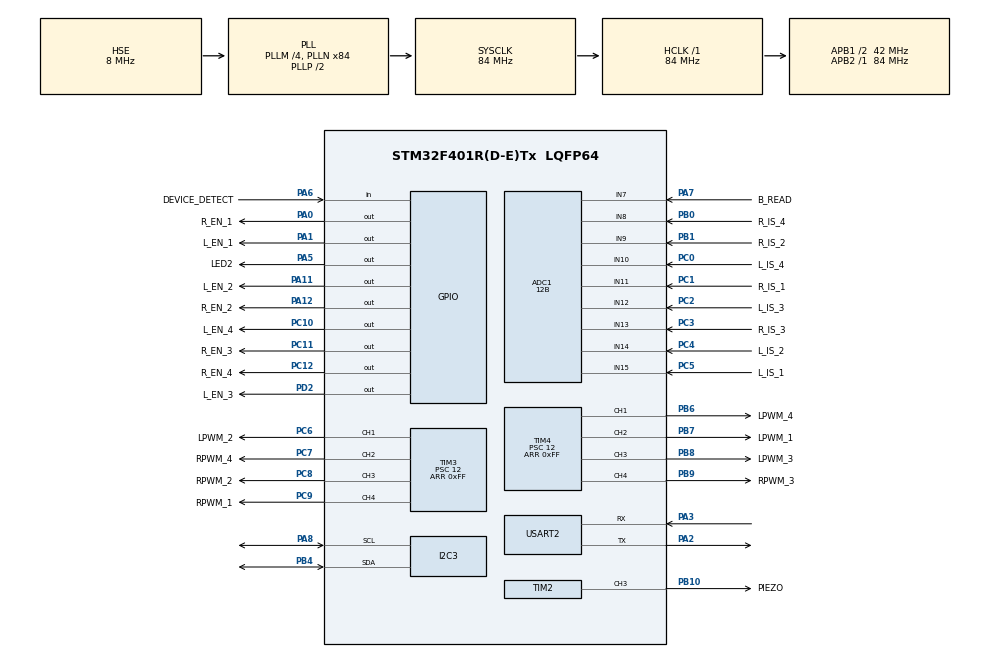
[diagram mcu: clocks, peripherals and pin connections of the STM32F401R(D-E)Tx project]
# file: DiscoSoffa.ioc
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ADC1.Channel-10\#ChannelRegularConversion=ADC_CHANNEL_13
ADC1.Channel-11\#ChannelRegularConversion=ADC_CHANNEL_14
ADC1.Channel-12\#ChannelRegularConversion=ADC_CHANNEL_15
ADC1.Channel-4\#ChannelRegularConversion=ADC_CHANNEL_7
ADC1.Channel-5\#ChannelRegularConversion=ADC_CHANNEL_8
ADC1.Channel-6\#ChannelRegularConversion=ADC_CHANNEL_9
ADC1.Channel-7\#ChannelRegularConversion=ADC_CHANNEL_10
ADC1.Channel-8\#ChannelRegularConversion=ADC_CHANNEL_11
ADC1.Channel-9\#ChannelRegularConversion=ADC_CHANNEL_12
ADC1.ContinuousConvMode=ENABLE
ADC1.DMAContinuousRequests=ENABLE
ADC1.NbrOfConversion=9
ADC1.NbrOfConversionFlag=1
ADC1.Rank-10\#ChannelRegularConversion=7
ADC1.Rank-11\#ChannelRegularConversion=8
ADC1.Rank-12\#ChannelRegularConversion=9
ADC1.Rank-4\#ChannelRegularConversion=1
ADC1.Rank-5\#ChannelRegularConversion=2
ADC1.Rank-6\#ChannelRegularConversion=3
ADC1.Rank-7\#ChannelRegularConversion=4
ADC1.Rank-8\#ChannelRegularConversion=5
ADC1.Rank-9\#ChannelRegularConversion=6
ADC1.Resolution=ADC_RESOLUTION_12B
ADC1.SamplingTime-10\#ChannelRegularConversion=ADC_SAMPLETIME_56CYCLES
ADC1.SamplingTime-11\#ChannelRegularConversion=ADC_SAMPLETIME_56CYCLES
ADC1.SamplingTime-12\#ChannelRegularConversion=ADC_SAMPLETIME_56CYCLES
ADC1.SamplingTime-4\#ChannelRegularConversion=ADC_SAMPLETIME_56CYCLES
ADC1.SamplingTime-5\#ChannelRegularConversion=ADC_SAMPLETIME_56CYCLES
ADC1.SamplingTime-6\#ChannelRegularConversion=ADC_SAMPLETIME_56CYCLES
ADC1.SamplingTime-7\#ChannelRegularConversion=ADC_SAMPLETIME_56CYCLES
ADC1.SamplingTime-8\#ChannelRegularConversion=ADC_SAMPLETIME_56CYCLES
ADC1.SamplingTime-9\#ChannelRegularConversion=ADC_SAMPLETIME_56CYCLES
ADC1.ScanConvMode=ENABLE
ADC1.master=1
Dma.ADC1.0.Direction=DMA_PERIPH_TO_MEMORY
Dma.ADC1.0.FIFOMode=DMA_FIFOMODE_DISABLE
Dma.ADC1.0.Instance=DMA2_Stream0
Dma.ADC1.0.MemDataAlignment=DMA_MDATAALIGN_HALFWORD
Dma.ADC1.0.MemInc=DMA_MINC_ENABLE
Dma.ADC1.0.Mode=DMA_CIRCULAR
Dma.ADC1.0.PeriphDataAlignment=DMA_PDATAALIGN_HALFWORD
Dma.ADC1.0.PeriphInc=DMA_PINC_DISABLE
Dma.ADC1.0.Priority=DMA_PRIORITY_HIGH
Dma.Request0=ADC1
Mcu.Family=STM32F4
Mcu.Name=STM32F401R(D-E)Tx
Mcu.Package=LQFP64
NVIC.ADC_IRQn=true\:0\:0\:false\:false\:true\:true\:true
NVIC.DMA2_Stream0_IRQn=true\:0\:0\:false\:false\:true\:false\:true
NVIC.I2C3_ER_IRQn=true\:0\:0\:false\:false\:true\:true\:true
NVIC.I2C3_EV_IRQn=true\:0\:0\:false\:false\:true\:true\:true
NVIC.PriorityGroup=NVIC_PRIORITYGROUP_4
PA0-WKUP.GPIO_Label=R_EN_1
PA0-WKUP.Signal=GPIO_Output
PA1.GPIO_Label=L_EN_1
PA1.Signal=GPIO_Output
PA11.GPIO_Label=L_EN_2
PA11.Signal=GPIO_Output
PA12.GPIO_Label=R_EN_2
PA12.Signal=GPIO_Output
PA13.Mode=Trace_Asynchronous_SW
PA13.Signal=SYS_JTMS-SWDIO
PA14.Mode=Trace_Asynchronous_SW
PA14.Signal=SYS_JTCK-SWCLK
PA2.Mode=Asynchronous
PA2.Signal=USART2_TX
PA3.Mode=Asynchronous
PA3.Signal=USART2_RX
PA5.GPIO_Label=LED2
PA5.Signal=GPIO_Output
PA6.GPIO_Label=DEVICE_DETECT
PA6.Signal=GPIO_Input
PA7.GPIO_Label=B_READ
PA7.Signal=ADCx_IN7
PA8.Mode=I2C
PA8.Signal=I2C3_SCL
PB0.GPIO_Label=R_IS_4
PB0.Signal=ADCx_IN8
PB1.GPIO_Label=R_IS_2
PB1.Signal=ADCx_IN9
PB10.GPIO_Label=PIEZO
PB10.Signal=S_TIM2_CH3
PB3.Mode=Trace_Asynchronous_SW
PB3.Signal=SYS_JTDO-SWO
PB4.Mode=I2C
PB4.Signal=I2C3_SDA
PB6.GPIO_Label=LPWM_4
PB6.Signal=S_TIM4_CH1
PB7.GPIO_Label=LPWM_1
PB7.Signal=S_TIM4_CH2
PB8.GPIO_Label=LPWM_3
PB8.Signal=S_TIM4_CH3
PB9.GPIO_Label=RPWM_3
PB9.Signal=S_TIM4_CH4
PC0.GPIO_Label=L_IS_4
PC0.Signal=ADCx_IN10
PC1.GPIO_Label=R_IS_1
PC1.Signal=ADCx_IN11
PC10.GPIO_Label=L_EN_4
PC10.Signal=GPIO_Output
PC11.GPIO_Label=R_EN_3
PC11.Signal=GPIO_Output
PC12.GPIO_Label=R_EN_4
PC12.Signal=GPIO_Output
PC2.GPIO_Label=L_IS_3
PC2.Signal=ADCx_IN12
PC3.GPIO_Label=R_IS_3
PC3.Signal=ADCx_IN13
PC4.GPIO_Label=L_IS_2
PC4.Signal=ADCx_IN14
PC5.GPIO_Label=L_IS_1
PC5.Signal=ADCx_IN15
PC6.GPIO_Label=LPWM_2
PC6.Signal=S_TIM3_CH1
PC7.GPIO_Label=RPWM_4
PC7.Signal=S_TIM3_CH2
PC8.GPIO_Label=RPWM_2
PC8.Signal=S_TIM3_CH3
PC9.GPIO_Label=RPWM_1
PC9.Signal=S_TIM3_CH4
PD2.GPIO_Label=L_EN_3
PD2.Signal=GPIO_Output
PH0\ -\ OSC_IN.Mode=HSE-External-Clock-Source
PH0\ -\ OSC_IN.Signal=RCC_OSC_IN
PH1\ -\ OSC_OUT.Mode=HSE-External-Clock-Source
PH1\ -\ OSC_OUT.Signal=RCC_OSC_OUT
ProjectManager.HeapSize=0x200
ProjectManager.StackSize=0x400
ProjectManager.TargetToolchain=TrueSTUDIO
RCC.48MHZClocksFreq_Value=42000000
RCC.AHBFreq_Value=84000000
RCC.APB1CLKDivider=RCC_HCLK_DIV2
RCC.APB1Freq_Value=42000000
RCC.APB1TimFreq_Value=84000000
RCC.APB2Freq_Value=84000000
RCC.APB2TimFreq_Value=84000000
RCC.CortexFreq_Value=84000000
RCC.HCLKFreq_Value=84000000
RCC.HSE_VALUE=8000000
RCC.HSI_VALUE=16000000
RCC.LSE_VALUE=32768
RCC.PLLM=4
RCC.PLLN=84
RCC.PLLSourceVirtual=RCC_PLLSOURCE_HSE
RCC.SYSCLKFreq_VALUE=84000000
RCC.SYSCLKSource=RCC_SYSCLKSOURCE_PLLCLK
RCC.VCOOutputFreq_Value=168000000
SH.ADCx_IN10.0=ADC1_IN10,IN10
SH.ADCx_IN11.0=ADC1_IN11,IN11
SH.ADCx_IN12.0=ADC1_IN12,IN12
SH.ADCx_IN13.0=ADC1_IN13,IN13
SH.ADCx_IN14.0=ADC1_IN14,IN14
SH.ADCx_IN15.0=ADC1_IN15,IN15
SH.ADCx_IN7.0=ADC1_IN7,IN7
SH.ADCx_IN8.0=ADC1_IN8,IN8
SH.ADCx_IN9.0=ADC1_IN9,IN9
SH.S_TIM2_CH3.0=TIM2_CH3,PWM Generation3 CH3
SH.S_TIM3_CH1.0=TIM3_CH1,PWM Generation1 CH1
SH.S_TIM3_CH2.0=TIM3_CH2,PWM Generation2 CH2
SH.S_TIM3_CH3.0=TIM3_CH3,PWM Generation3 CH3
SH.S_TIM3_CH4.0=TIM3_CH4,PWM Generation4 CH4
SH.S_TIM4_CH1.0=TIM4_CH1,PWM Generation1 CH1
SH.S_TIM4_CH2.0=TIM4_CH2,PWM Generation2 CH2
SH.S_TIM4_CH3.0=TIM4_CH3,PWM Generation3 CH3
SH.S_TIM4_CH4.0=TIM4_CH4,PWM Generation4 CH4
TIM2.Channel-PWM\ Generation3\ CH3=TIM_CHANNEL_3
TIM2.OCFastMode_PWM-PWM\ Generation3\ CH3=TIM_OCFAST_ENABLE
TIM2.Period=65536
TIM2.Pulse-PWM\ Generation3\ CH3=32768
TIM3.Channel-PWM\ Generation1\ CH1=TIM_CHANNEL_1
TIM3.Channel-PWM\ Generation2\ CH2=TIM_CHANNEL_2
TIM3.Channel-PWM\ Generation3\ CH3=TIM_CHANNEL_3
TIM3.Channel-PWM\ Generation4\ CH4=TIM_CHANNEL_4
TIM3.OCFastMode_PWM-PWM\ Generation1\ CH1=TIM_OCFAST_ENABLE
TIM3.OCFastMode_PWM-PWM\ Generation2\ CH2=TIM_OCFAST_ENABLE
TIM3.OCFastMode_PWM-PWM\ Generation3\ CH3=TIM_OCFAST_ENABLE
TIM3.OCFastMode_PWM-PWM\ Generation4\ CH4=TIM_OCFAST_ENABLE
TIM3.Period=0xFF
TIM3.Prescaler=12
TIM3.Pulse-PWM\ Generation1\ CH1=0x80
TIM4.Channel-PWM\ Generation1\ CH1=TIM_CHANNEL_1
TIM4.Channel-PWM\ Generation2\ CH2=TIM_CHANNEL_2
TIM4.Channel-PWM\ Generation3\ CH3=TIM_CHANNEL_3
TIM4.Channel-PWM\ Generation4\ CH4=TIM_CHANNEL_4
TIM4.OCFastMode_PWM-PWM\ Generation1\ CH1=TIM_OCFAST_ENABLE
TIM4.OCFastMode_PWM-PWM\ Generation2\ CH2=TIM_OCFAST_ENABLE
TIM4.OCFastMode_PWM-PWM\ Generation3\ CH3=TIM_OCFAST_ENABLE
TIM4.OCFastMode_PWM-PWM\ Generation4\ CH4=TIM_OCFAST_ENABLE
TIM4.Period=0xFF
TIM4.Prescaler=12
USART2.VirtualMode=VM_ASYNC
VP_TIM2_VS_ClockSourceINT.Mode=Internal
VP_TIM3_VS_ClockSourceINT.Mode=Internal
VP_TIM4_VS_ClockSourceINT.Mode=Internal
board=custom

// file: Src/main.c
/* USER CODE BEGIN Header */
/**
  ******************************************************************************
  * @file           : main.c
  * @brief          : Main program body
  ******************************************************************************
  * @attention
  *
  * <h2><center>&copy; Copyright (c) 2019 STMicroelectronics.
  * All rights reserved.</center></h2>
  *
  * This software component is licensed by ST under BSD 3-Clause license,
  * the "License"; You may not use this file except in compliance with the
  * License. You may obtain a copy of the License at:
  *                        opensource.org/licenses/BSD-3-Clause
  *
  ******************************************************************************
  */
/* USER CODE END Header */

#include "main.h"

ADC_HandleTypeDef hadc1;
DMA_HandleTypeDef hdma_adc1;

I2C_HandleTypeDef hi2c3;

TIM_HandleTypeDef htim2;
TIM_HandleTypeDef htim3;
TIM_HandleTypeDef htim4;

UART_HandleTypeDef huart2;

/* USER CODE BEGIN PV */

NUNCHUCK_HandleTypeDef nun1;

MOTOR_HandleTypeDef motor1;
MOTOR_HandleTypeDef motor2;
MOTOR_HandleTypeDef motor3;
MOTOR_HandleTypeDef motor4;

BOARD_BuzzerHandlerTypeDef buzzer;
BOARD_BatteryVoltageHandlerTypedef hbat;

uint8_t uartBuffer[50];
uint16_t adcBuffer[9];

uint8_t speed;
uint8_t leftSpeed;
uint8_t rightSpeed;

MOTOR_ModeTypeDef motorMode;

/* USER CODE END PV */

void SystemClock_Config(void);
static void MX_GPIO_Init(void);
static void MX_DMA_Init(void);
static void MX_ADC1_Init(void);
static void MX_I2C3_Init(void);
static void MX_TIM2_Init(void);
static void MX_TIM3_Init(void);
static void MX_TIM4_Init(void);
static void MX_USART2_UART_Init(void);
/* USER CODE BEGIN PFP */

static void MX_BOARD_Init(void);
static void MX_MOTOR_Init(void);
static void MX_NUNCHUCK_Init(void);

/* USER CODE END PFP */

int main(void)
{

  /* MCU Configuration--------------------------------------------------------*/

  /* Reset of all peripherals, Initializes the Flash interface and the Systick. */
  HAL_Init();

  /* Configure the system clock */
  SystemClock_Config();

  /* Initialize all configured peripherals */
  MX_GPIO_Init();
  MX_DMA_Init();
  MX_ADC1_Init();
  MX_I2C3_Init();
  MX_TIM2_Init();
  MX_TIM3_Init();
  MX_TIM4_Init();
  MX_USART2_UART_Init();
  /* USER CODE BEGIN 2 */
  /* Initialize drivers */
  MX_BOARD_Init();
  MX_MOTOR_Init();
  MX_NUNCHUCK_Init();

  /* Play startup sound */
  HAL_BOARD_BuzzerBeep(&buzzer,440,200);
  HAL_BOARD_BuzzerBeep(&buzzer,440*2,200);
  HAL_BOARD_BuzzerBeep(&buzzer,440*3,200);
  HAL_BOARD_BuzzerBeep(&buzzer,440*4,200);
  HAL_BOARD_BuzzerBeep(&buzzer,440,300);

  /* Start ADC DMA */
  HAL_ADC_Start_DMA(&hadc1, (uint32_t *) adcBuffer, 9);

  /* USER CODE END 2 */

  /* Infinite loop */
  while (1)
  {

    /* USER CODE BEGIN 3 */

	  HAL_NUNCHUCK_Read(&nun1);

	  if(nun1.Connected != 1)
	  {
		  if((nun1.zButton != 1) || (nun1.cButton == 1))
		  {
			  motorMode = HAL_MOTOR_MODE_BREAK;
		  }
		  else if(nun1.yJoy == 0)
		  {
			  motorMode = HAL_MOTOR_MODE_DISABLE;
		  }
		  else if(nun1.yJoy > 0)
		  {
			  motorMode = HAL_MOTOR_MODE_FORWARD;
			  speed = nun1.yJoy*0xFF;
		  }
		  else if(nun1.yJoy < 0)
		  {
			  motorMode = HAL_MOTOR_MODE_REVERSE;
			  speed = -nun1.yJoy*0xFF;
		  }

		  if(nun1.xJoy > 0)
		  {
			  leftSpeed = speed;
			  rightSpeed = (1.0f-nun1.xJoy)*speed;
		  }
		  else if(nun1.xJoy < 0)
		  {
			  rightSpeed = speed;
			  leftSpeed = (1.0f+nun1.xJoy)*speed;
		  }
		  else
		  {
			  rightSpeed = speed;
			  leftSpeed = speed;
		  }
	  }
	  else
	  {
		  motorMode = HAL_MOTOR_MODE_BREAK;
		  speed = 0;
		  rightSpeed = 0;
		  leftSpeed = 0;
	  }
	  motor1.TargetDuty = rightSpeed;
	  motor3.TargetDuty = rightSpeed;

	  motor2.TargetDuty = leftSpeed;
	  motor4.TargetDuty = leftSpeed;

	  motor1.TargetMotorMode = motorMode;
	  motor2.TargetMotorMode = motorMode;
	  motor3.TargetMotorMode = motorMode;
	  motor4.TargetMotorMode = motorMode;

	  HAL_MOTOR_Update(&motor1);
	  HAL_MOTOR_Update(&motor2);
	  HAL_MOTOR_Update(&motor3);
	  HAL_MOTOR_Update(&motor4);

	  HAL_Delay(20);
  }
  /* USER CODE END 3 */
}

void SystemClock_Config(void)
{
  RCC_OscInitTypeDef RCC_OscInitStruct = {0};
  RCC_ClkInitTypeDef RCC_ClkInitStruct = {0};

  /** Configure the main internal regulator output voltage
  */
  __HAL_RCC_PWR_CLK_ENABLE();
  __HAL_PWR_VOLTAGESCALING_CONFIG(PWR_REGULATOR_VOLTAGE_SCALE2);
  /** Initializes the CPU, AHB and APB busses clocks
  */
  RCC_OscInitStruct.OscillatorType = RCC_OSCILLATORTYPE_HSE;
  RCC_OscInitStruct.HSEState = RCC_HSE_BYPASS;
  RCC_OscInitStruct.PLL.PLLState = RCC_PLL_ON;
  RCC_OscInitStruct.PLL.PLLSource = RCC_PLLSOURCE_HSE;
  RCC_OscInitStruct.PLL.PLLM = 4;
  RCC_OscInitStruct.PLL.PLLN = 84;
  RCC_OscInitStruct.PLL.PLLP = RCC_PLLP_DIV2;
  RCC_OscInitStruct.PLL.PLLQ = 4;
  if (HAL_RCC_OscConfig(&RCC_OscInitStruct) != HAL_OK)
  {
    Error_Handler();
  }
  /** Initializes the CPU, AHB and APB busses clocks
  */
  RCC_ClkInitStruct.ClockType = RCC_CLOCKTYPE_HCLK|RCC_CLOCKTYPE_SYSCLK
                              |RCC_CLOCKTYPE_PCLK1|RCC_CLOCKTYPE_PCLK2;
  RCC_ClkInitStruct.SYSCLKSource = RCC_SYSCLKSOURCE_PLLCLK;
  RCC_ClkInitStruct.AHBCLKDivider = RCC_SYSCLK_DIV1;
  RCC_ClkInitStruct.APB1CLKDivider = RCC_HCLK_DIV2;
  RCC_ClkInitStruct.APB2CLKDivider = RCC_HCLK_DIV1;

  if (HAL_RCC_ClockConfig(&RCC_ClkInitStruct, FLASH_LATENCY_2) != HAL_OK)
  {
    Error_Handler();
  }
}

static void MX_ADC1_Init(void)
{

  ADC_ChannelConfTypeDef sConfig = {0};

  /** Configure the global features of the ADC (Clock, Resolution, Data Alignment and number of conversion)
  */
  hadc1.Instance = ADC1;
  hadc1.Init.ClockPrescaler = ADC_CLOCK_SYNC_PCLK_DIV4;
  hadc1.Init.Resolution = ADC_RESOLUTION_12B;
  hadc1.Init.ScanConvMode = ENABLE;
  hadc1.Init.ContinuousConvMode = ENABLE;
  hadc1.Init.DiscontinuousConvMode = DISABLE;
  hadc1.Init.ExternalTrigConvEdge = ADC_EXTERNALTRIGCONVEDGE_NONE;
  hadc1.Init.ExternalTrigConv = ADC_SOFTWARE_START;
  hadc1.Init.DataAlign = ADC_DATAALIGN_RIGHT;
  hadc1.Init.NbrOfConversion = 9;
  hadc1.Init.DMAContinuousRequests = ENABLE;
  hadc1.Init.EOCSelection = ADC_EOC_SINGLE_CONV;
  if (HAL_ADC_Init(&hadc1) != HAL_OK)
  {
    Error_Handler();
  }
  /** Configure for the selected ADC regular channel its corresponding rank in the sequencer and its sample time.
  */
  sConfig.Channel = ADC_CHANNEL_7;
  sConfig.Rank = 1;
  sConfig.SamplingTime = ADC_SAMPLETIME_56CYCLES;
  if (HAL_ADC_ConfigChannel(&hadc1, &sConfig) != HAL_OK)
  {
    Error_Handler();
  }
  /** Configure for the selected ADC regular channel its corresponding rank in the sequencer and its sample time.
  */
  sConfig.Channel = ADC_CHANNEL_8;
  sConfig.Rank = 2;
  if (HAL_ADC_ConfigChannel(&hadc1, &sConfig) != HAL_OK)
  {
    Error_Handler();
  }
  /** Configure for the selected ADC regular channel its corresponding rank in the sequencer and its sample time.
  */
  sConfig.Channel = ADC_CHANNEL_9;
  sConfig.Rank = 3;
  if (HAL_ADC_ConfigChannel(&hadc1, &sConfig) != HAL_OK)
  {
    Error_Handler();
  }
  /** Configure for the selected ADC regular channel its corresponding rank in the sequencer and its sample time.
  */
  sConfig.Channel = ADC_CHANNEL_10;
  sConfig.Rank = 4;
  if (HAL_ADC_ConfigChannel(&hadc1, &sConfig) != HAL_OK)
  {
    Error_Handler();
  }
  /** Configure for the selected ADC regular channel its corresponding rank in the sequencer and its sample time.
  */
  sConfig.Channel = ADC_CHANNEL_11;
  sConfig.Rank = 5;
  if (HAL_ADC_ConfigChannel(&hadc1, &sConfig) != HAL_OK)
  {
    Error_Handler();
  }
  /** Configure for the selected ADC regular channel its corresponding rank in the sequencer and its sample time.
  */
  sConfig.Channel = ADC_CHANNEL_12;
  sConfig.Rank = 6;
  if (HAL_ADC_ConfigChannel(&hadc1, &sConfig) != HAL_OK)
  {
    Error_Handler();
  }
  /** Configure for the selected ADC regular channel its corresponding rank in the sequencer and its sample time.
  */
  sConfig.Channel = ADC_CHANNEL_13;
  sConfig.Rank = 7;
  if (HAL_ADC_ConfigChannel(&hadc1, &sConfig) != HAL_OK)
  {
    Error_Handler();
  }
  /** Configure for the selected ADC regular channel its corresponding rank in the sequencer and its sample time.
  */
  sConfig.Channel = ADC_CHANNEL_14;
  sConfig.Rank = 8;
  if (HAL_ADC_ConfigChannel(&hadc1, &sConfig) != HAL_OK)
  {
    Error_Handler();
  }
  /** Configure for the selected ADC regular channel its corresponding rank in the sequencer and its sample time.
  */
  sConfig.Channel = ADC_CHANNEL_15;
  sConfig.Rank = 9;
  if (HAL_ADC_ConfigChannel(&hadc1, &sConfig) != HAL_OK)
  {
    Error_Handler();
  }

}

static void MX_I2C3_Init(void)
{

  hi2c3.Instance = I2C3;
  hi2c3.Init.ClockSpeed = 100000;
  hi2c3.Init.DutyCycle = I2C_DUTYCYCLE_2;
  hi2c3.Init.OwnAddress1 = 0;
  hi2c3.Init.AddressingMode = I2C_ADDRESSINGMODE_7BIT;
  hi2c3.Init.DualAddressMode = I2C_DUALADDRESS_DISABLE;
  hi2c3.Init.OwnAddress2 = 0;
  hi2c3.Init.GeneralCallMode = I2C_GENERALCALL_DISABLE;
  hi2c3.Init.NoStretchMode = I2C_NOSTRETCH_DISABLE;
  if (HAL_I2C_Init(&hi2c3) != HAL_OK)
  {
    Error_Handler();
  }

}

static void MX_TIM2_Init(void)
{

  TIM_ClockConfigTypeDef sClockSourceConfig = {0};
  TIM_MasterConfigTypeDef sMasterConfig = {0};
  TIM_OC_InitTypeDef sConfigOC = {0};

  htim2.Instance = TIM2;
  htim2.Init.Prescaler = 0;
  htim2.Init.CounterMode = TIM_COUNTERMODE_UP;
  htim2.Init.Period = 65536;
  htim2.Init.ClockDivision = TIM_CLOCKDIVISION_DIV1;
  htim2.Init.AutoReloadPreload = TIM_AUTORELOAD_PRELOAD_DISABLE;
  if (HAL_TIM_Base_Init(&htim2) != HAL_OK)
  {
    Error_Handler();
  }
  sClockSourceConfig.ClockSource = TIM_CLOCKSOURCE_INTERNAL;
  if (HAL_TIM_ConfigClockSource(&htim2, &sClockSourceConfig) != HAL_OK)
  {
    Error_Handler();
  }
  if (HAL_TIM_PWM_Init(&htim2) != HAL_OK)
  {
    Error_Handler();
  }
  sMasterConfig.MasterOutputTrigger = TIM_TRGO_RESET;
  sMasterConfig.MasterSlaveMode = TIM_MASTERSLAVEMODE_DISABLE;
  if (HAL_TIMEx_MasterConfigSynchronization(&htim2, &sMasterConfig) != HAL_OK)
  {
    Error_Handler();
  }
  sConfigOC.OCMode = TIM_OCMODE_PWM1;
  sConfigOC.Pulse = 32768;
  sConfigOC.OCPolarity = TIM_OCPOLARITY_HIGH;
  sConfigOC.OCFastMode = TIM_OCFAST_ENABLE;
  if (HAL_TIM_PWM_ConfigChannel(&htim2, &sConfigOC, TIM_CHANNEL_3) != HAL_OK)
  {
    Error_Handler();
  }
  HAL_TIM_MspPostInit(&htim2);

}

static void MX_TIM3_Init(void)
{

  TIM_ClockConfigTypeDef sClockSourceConfig = {0};
  TIM_MasterConfigTypeDef sMasterConfig = {0};
  TIM_OC_InitTypeDef sConfigOC = {0};

  htim3.Instance = TIM3;
  htim3.Init.Prescaler = 30;
  htim3.Init.CounterMode = TIM_COUNTERMODE_UP;
  htim3.Init.Period = 0xFF;
  htim3.Init.ClockDivision = TIM_CLOCKDIVISION_DIV1;
  htim3.Init.AutoReloadPreload = TIM_AUTORELOAD_PRELOAD_DISABLE;
  if (HAL_TIM_Base_Init(&htim3) != HAL_OK)
  {
    Error_Handler();
  }
  sClockSourceConfig.ClockSource = TIM_CLOCKSOURCE_INTERNAL;
  if (HAL_TIM_ConfigClockSource(&htim3, &sClockSourceConfig) != HAL_OK)
  {
    Error_Handler();
  }
  if (HAL_TIM_PWM_Init(&htim3) != HAL_OK)
  {
    Error_Handler();
  }
  sMasterConfig.MasterOutputTrigger = TIM_TRGO_RESET;
  sMasterConfig.MasterSlaveMode = TIM_MASTERSLAVEMODE_DISABLE;
  if (HAL_TIMEx_MasterConfigSynchronization(&htim3, &sMasterConfig) != HAL_OK)
  {
    Error_Handler();
  }
  sConfigOC.OCMode = TIM_OCMODE_PWM1;
  sConfigOC.Pulse = 0x80;
  sConfigOC.OCPolarity = TIM_OCPOLARITY_HIGH;
  sConfigOC.OCFastMode = TIM_OCFAST_ENABLE;
  if (HAL_TIM_PWM_ConfigChannel(&htim3, &sConfigOC, TIM_CHANNEL_1) != HAL_OK)
  {
    Error_Handler();
  }
  sConfigOC.Pulse = 0;
  if (HAL_TIM_PWM_ConfigChannel(&htim3, &sConfigOC, TIM_CHANNEL_2) != HAL_OK)
  {
    Error_Handler();
  }
  if (HAL_TIM_PWM_ConfigChannel(&htim3, &sConfigOC, TIM_CHANNEL_3) != HAL_OK)
  {
    Error_Handler();
  }
  if (HAL_TIM_PWM_ConfigChannel(&htim3, &sConfigOC, TIM_CHANNEL_4) != HAL_OK)
  {
    Error_Handler();
  }
  HAL_TIM_MspPostInit(&htim3);

}

static void MX_TIM4_Init(void)
{

  TIM_ClockConfigTypeDef sClockSourceConfig = {0};
  TIM_MasterConfigTypeDef sMasterConfig = {0};
  TIM_OC_InitTypeDef sConfigOC = {0};

  htim4.Instance = TIM4;
  htim4.Init.Prescaler = 30;
  htim4.Init.CounterMode = TIM_COUNTERMODE_UP;
  htim4.Init.Period = 0xFF;
  htim4.Init.ClockDivision = TIM_CLOCKDIVISION_DIV1;
  htim4.Init.AutoReloadPreload = TIM_AUTORELOAD_PRELOAD_DISABLE;
  if (HAL_TIM_Base_Init(&htim4) != HAL_OK)
  {
    Error_Handler();
  }
  sClockSourceConfig.ClockSource = TIM_CLOCKSOURCE_INTERNAL;
  if (HAL_TIM_ConfigClockSource(&htim4, &sClockSourceConfig) != HAL_OK)
  {
    Error_Handler();
  }
  if (HAL_TIM_PWM_Init(&htim4) != HAL_OK)
  {
    Error_Handler();
  }
  sMasterConfig.MasterOutputTrigger = TIM_TRGO_RESET;
  sMasterConfig.MasterSlaveMode = TIM_MASTERSLAVEMODE_DISABLE;
  if (HAL_TIMEx_MasterConfigSynchronization(&htim4, &sMasterConfig) != HAL_OK)
  {
    Error_Handler();
  }
  sConfigOC.OCMode = TIM_OCMODE_PWM1;
  sConfigOC.Pulse = 0;
  sConfigOC.OCPolarity = TIM_OCPOLARITY_HIGH;
  sConfigOC.OCFastMode = TIM_OCFAST_ENABLE;
  if (HAL_TIM_PWM_ConfigChannel(&htim4, &sConfigOC, TIM_CHANNEL_1) != HAL_OK)
  {
    Error_Handler();
  }
  if (HAL_TIM_PWM_ConfigChannel(&htim4, &sConfigOC, TIM_CHANNEL_2) != HAL_OK)
  {
    Error_Handler();
  }
  if (HAL_TIM_PWM_ConfigChannel(&htim4, &sConfigOC, TIM_CHANNEL_3) != HAL_OK)
  {
    Error_Handler();
  }
  if (HAL_TIM_PWM_ConfigChannel(&htim4, &sConfigOC, TIM_CHANNEL_4) != HAL_OK)
  {
    Error_Handler();
  }
  HAL_TIM_MspPostInit(&htim4);

}

static void MX_USART2_UART_Init(void)
{

  huart2.Instance = USART2;
  huart2.Init.BaudRate = 115200;
  huart2.Init.WordLength = UART_WORDLENGTH_8B;
  huart2.Init.StopBits = UART_STOPBITS_1;
  huart2.Init.Parity = UART_PARITY_NONE;
  huart2.Init.Mode = UART_MODE_TX_RX;
  huart2.Init.HwFlowCtl = UART_HWCONTROL_NONE;
  huart2.Init.OverSampling = UART_OVERSAMPLING_16;
  if (HAL_UART_Init(&huart2) != HAL_OK)
  {
    Error_Handler();
  }

}

static void MX_DMA_Init(void)
{
  /* DMA controller clock enable */
  __HAL_RCC_DMA2_CLK_ENABLE();

  /* DMA interrupt init */
  /* DMA2_Stream0_IRQn interrupt configuration */
  HAL_NVIC_SetPriority(DMA2_Stream0_IRQn, 0, 0);
  HAL_NVIC_EnableIRQ(DMA2_Stream0_IRQn);

}

static void MX_GPIO_Init(void)
{
  GPIO_InitTypeDef GPIO_InitStruct = {0};

  /* GPIO Ports Clock Enable */
  __HAL_RCC_GPIOH_CLK_ENABLE();
  __HAL_RCC_GPIOC_CLK_ENABLE();
  __HAL_RCC_GPIOA_CLK_ENABLE();
  __HAL_RCC_GPIOB_CLK_ENABLE();

  /*Configure GPIO pin Output Level */
  HAL_GPIO_WritePin(GPIOA, EN_1_Pin|LED2_Pin|EN_2_Pin, GPIO_PIN_RESET);

  /*Configure GPIO pin Output Level */
  HAL_GPIO_WritePin(GPIOC, EN_3_Pin|EN_4_Pin, GPIO_PIN_RESET);

  /*Configure GPIO pins : EN_1_Pin LED2_Pin EN_2_Pin */
  GPIO_InitStruct.Pin = EN_1_Pin|LED2_Pin|EN_2_Pin;
  GPIO_InitStruct.Mode = GPIO_MODE_OUTPUT_PP;
  GPIO_InitStruct.Pull = GPIO_NOPULL;
  GPIO_InitStruct.Speed = GPIO_SPEED_FREQ_LOW;
  HAL_GPIO_Init(GPIOA, &GPIO_InitStruct);

  /*Configure GPIO pin : DEVICE_DETECT_Pin */
  GPIO_InitStruct.Pin = DEVICE_DETECT_Pin;
  GPIO_InitStruct.Mode = GPIO_MODE_INPUT;
  GPIO_InitStruct.Pull = GPIO_NOPULL;
  HAL_GPIO_Init(DEVICE_DETECT_GPIO_Port, &GPIO_InitStruct);

  /*Configure GPIO pins : EN_3_Pin EN_4_Pin */
  GPIO_InitStruct.Pin = EN_3_Pin|EN_4_Pin;
  GPIO_InitStruct.Mode = GPIO_MODE_OUTPUT_PP;
  GPIO_InitStruct.Pull = GPIO_NOPULL;
  GPIO_InitStruct.Speed = GPIO_SPEED_FREQ_LOW;
  HAL_GPIO_Init(GPIOC, &GPIO_InitStruct);

}

/* USER CODE BEGIN 4 */

static void MX_NUNCHUCK_Init(void)
{
	nun1.HI2C = &hi2c3;
    nun1.DeadZoneEnable = 1;
    nun1.xJoyDeadZone = 50;
    nun1.yJoyDeadZone = 50;

    HAL_NUNCHUCK_Calibrate(&nun1);
}

static void MX_MOTOR_Init(void)
{
	/* Motor 1 setup */
	motor1.RightHtim=&htim4;
	motor1.LeftHtim=&htim3;
	motor1.RightTimerChannel=TIM_CHANNEL_2;
	motor1.LeftTimerChannel=TIM_CHANNEL_4;
	motor1.CutOfCurrent = 10;
	motor1.MaxCurrent = 5;
	motor1.MaxDuty = 225;
	motor1.MinDuty = MIN_DUTY;
	motor1.DutyChangeFactor = DUTY_CHANGE_FACTOR;
	motor1.EnableGPIOTypeDef = EN_1_GPIO_Port;
	motor1.EnableGPIOPin = EN_1_Pin;
	motor1.RightCompareReg = &htim4.Instance->CCR2;
	motor1.LeftCompareReg = &htim3.Instance->CCR4;
	motor1.ModeChangeTick = MODE_CHANGE_TICKS;
	motor1.ISenseResistor = CURRENT_SENSE_RESISTOR;
	motor1.RawRightCurrent = &adcBuffer[4];
	motor1.RawLeftCurrent = &adcBuffer[8];
	HAL_MOTOR_Init(&motor1);

	/* Motor 2 setup */
	motor2.RightHtim=&htim3;
	motor2.LeftHtim=&htim3;
	motor2.RightTimerChannel=TIM_CHANNEL_1;
	motor2.LeftTimerChannel=TIM_CHANNEL_3;
	motor2.CutOfCurrent = CURRENT_DISABLE_LIMIT;
	motor2.MaxCurrent = CURRENT_REGULATION_LIMIT;
	motor2.MaxDuty = 225;
	motor2.MinDuty = MIN_DUTY;
	motor2.DutyChangeFactor = DUTY_CHANGE_FACTOR;
	motor2.EnableGPIOTypeDef = EN_2_GPIO_Port;
	motor2.EnableGPIOPin = EN_2_Pin;
	motor2.RightCompareReg = &htim3.Instance->CCR1;
	motor2.LeftCompareReg = &htim3.Instance->CCR3;
	motor2.ModeChangeTick = MODE_CHANGE_TICKS;
	motor2.ISenseResistor = CURRENT_SENSE_RESISTOR;
	motor2.RawRightCurrent = &adcBuffer[2];
	motor2.RawLeftCurrent = &adcBuffer[8];

	HAL_MOTOR_Init(&motor2);

	/* Motor 3 setup */
	motor3.RightHtim=&htim4;
	motor3.LeftHtim=&htim4;
	motor3.RightTimerChannel=TIM_CHANNEL_3;
	motor3.LeftTimerChannel=TIM_CHANNEL_4;
	motor3.CutOfCurrent = CURRENT_DISABLE_LIMIT;
	motor3.MaxCurrent = CURRENT_REGULATION_LIMIT;
	motor3.MaxDuty = 225;
	motor3.MinDuty = MIN_DUTY;
	motor3.DutyChangeFactor = DUTY_CHANGE_FACTOR;
	motor3.EnableGPIOTypeDef = EN_3_GPIO_Port;
	motor3.EnableGPIOPin = EN_3_Pin;
	motor3.RightCompareReg = &htim4.Instance->CCR3;
	motor3.LeftCompareReg = &htim4.Instance->CCR4;
	motor3.ModeChangeTick = MODE_CHANGE_TICKS;
	motor3.ISenseResistor = CURRENT_SENSE_RESISTOR;
	motor3.RawRightCurrent = &adcBuffer[2];
	motor3.RawLeftCurrent = &adcBuffer[6];

	HAL_MOTOR_Init(&motor3);

	/* Motor 4 setup */
	motor4.RightHtim=&htim4;
	motor4.LeftHtim=&htim3;
	motor4.RightTimerChannel=TIM_CHANNEL_1;
	motor4.LeftTimerChannel=TIM_CHANNEL_2;
	motor4.CutOfCurrent = CURRENT_DISABLE_LIMIT;
	motor4.MaxCurrent = CURRENT_REGULATION_LIMIT;
	motor4.MaxDuty = 225;
	motor4.MinDuty = MIN_DUTY;
	motor4.DutyChangeFactor = DUTY_CHANGE_FACTOR;
	motor4.EnableGPIOTypeDef = EN_4_GPIO_Port;
	motor4.EnableGPIOPin = EN_4_Pin;
	motor4.RightCompareReg = &htim4.Instance->CCR1;
	motor4.LeftCompareReg = &htim3.Instance->CCR2;
	motor4.ModeChangeTick = MODE_CHANGE_TICKS;
	motor4.ISenseResistor = CURRENT_SENSE_RESISTOR;
	motor4.RawRightCurrent = &adcBuffer[1];
	motor4.RawLeftCurrent = &adcBuffer[5];

	HAL_MOTOR_Init(&motor4);
}

static void MX_BOARD_Init(void)
{
	//Buzzer setup
	buzzer.Htim = &htim2;
	buzzer.TimerChannel = TIM_CHANNEL_3;

	//Battery voltage setup
	hbat.RawBatteryVoltage = &adcBuffer[0];
	hbat.ScalingFactor = 7.829;
}

/* USER CODE END 4 */

void Error_Handler(void)
{
}

/************************ (C) COPYRIGHT STMicroelectronics *****END OF FILE****/
